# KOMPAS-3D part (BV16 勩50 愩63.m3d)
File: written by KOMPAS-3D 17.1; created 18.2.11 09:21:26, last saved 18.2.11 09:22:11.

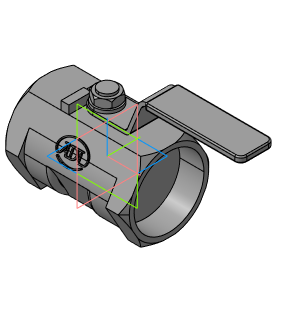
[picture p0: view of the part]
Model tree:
1. Плоскость XY
2. Плоскость ZX
3. Плоскость ZY
4. Ось X
5. Ось Y
6. Ось Z
7. Начало координат
8. Операция без истории:2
